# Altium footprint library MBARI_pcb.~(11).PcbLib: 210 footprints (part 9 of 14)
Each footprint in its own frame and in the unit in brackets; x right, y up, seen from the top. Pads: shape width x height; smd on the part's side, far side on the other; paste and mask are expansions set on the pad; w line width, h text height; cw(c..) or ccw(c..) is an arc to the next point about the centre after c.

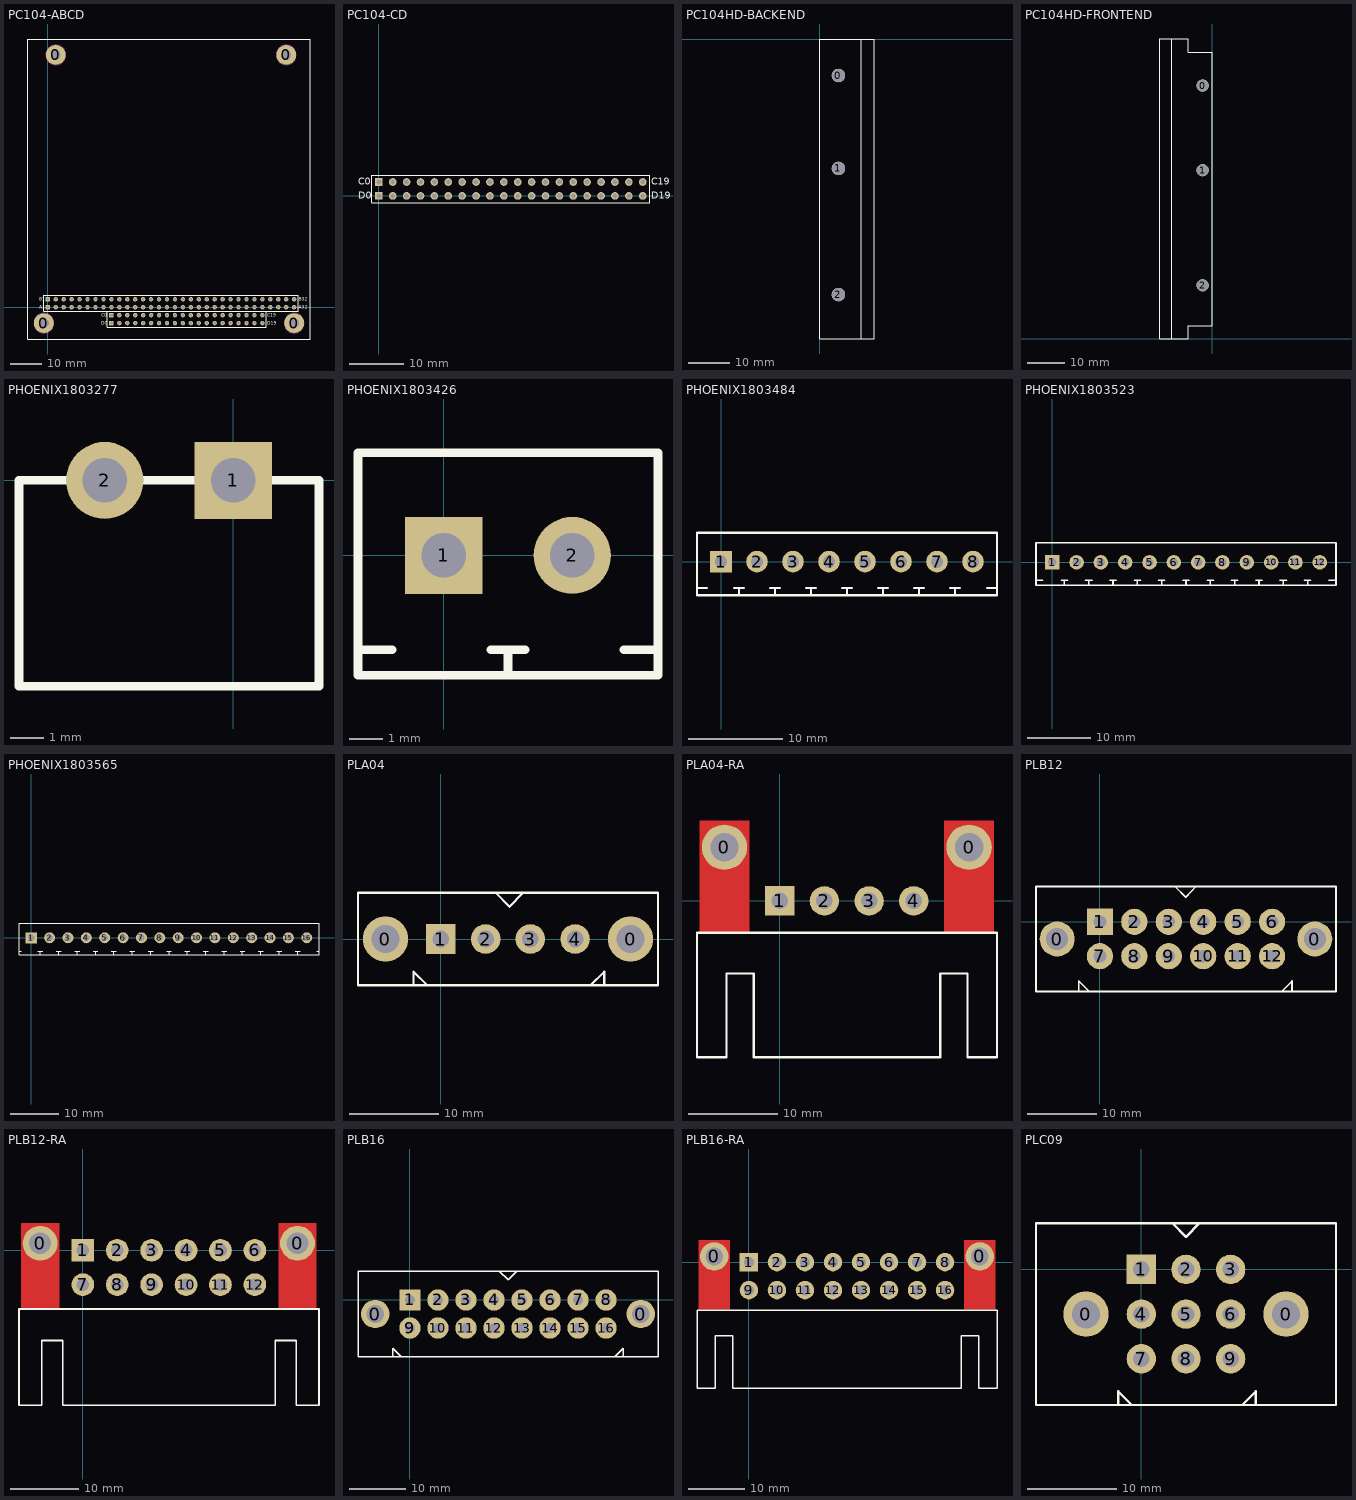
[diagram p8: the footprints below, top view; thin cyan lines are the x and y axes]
## PC104-ABCD [mil] "PC104 Outline and ABCD Rails"
height 600
pads (108):
  round 250 hole 125: 0(-50,-200) 0(100,3175) 0(3000,3175) 0(3100,-200)
  rect 55x55 hole 35: A1(0,0) B1(0,100) C0(800,-100) D0(800,-200)
  round 55 hole 35: A2(100,0) A3(200,0) A4(300,0) A5(400,0) A6(500,0) A7(600,0) A8(700,0) A9(800,0) A10(900,0) A11(1000,0) A12(1100,0) A13(1200,0) A14(1300,0) A15(1400,0) A16(1500,0) A17(1600,0) A18(1700,0) A19(1800,0) A20(1900,0) A21(2000,0) A22(2100,0) A23(2200,0) A24(2300,0) A25(2400,0) A26(2500,0) A27(2600,0) A28(2700,0) A29(2800,0) A30(2900,0) A31(3000,0) A32(3100,0) B2(100,100) B3(200,100) B4(300,100) B5(400,100) B6(500,100) B7(600,100) B8(700,100) B9(800,100) B10(900,100) B11(1000,100) B12(1100,100) B13(1200,100) B14(1300,100) B15(1400,100) B16(1500,100) B17(1600,100) B18(1700,100) B19(1800,100) B20(1900,100) B21(2000,100) B22(2100,100) B23(2200,100) B24(2300,100) B25(2400,100) B26(2500,100) B27(2600,100) B28(2700,100) B29(2800,100) B30(2900,100) B31(3000,100) B32(3100,100) C1(900,-100) C2(1000,-100) C3(1100,-100) C4(1200,-100) C5(1300,-100) C6(1400,-100) C7(1500,-100) C8(1600,-100) C9(1700,-100) C10(1800,-100) C11(1900,-100) C12(2000,-100) C13(2100,-100) C14(2200,-100) C15(2300,-100) C16(2400,-100) C17(2500,-100) C18(2600,-100) C19(2700,-100) D1(900,-200) D2(1000,-200) D3(1100,-200) D4(1200,-200) D5(1300,-200) D6(1400,-200) D7(1500,-200) D8(1600,-200) D9(1700,-200) D10(1800,-200) D11(1900,-200) D12(2000,-200) D13(2100,-200) D14(2200,-200) D15(2300,-200) D16(2400,-200) D17(2500,-200) D18(2600,-200) D19(2700,-200)
TopOverlay:
  lines w8: 3150,-50.39 3150,149.61 ; 3150,-50 -50,-50.39 -50,149.61 3150,150 ; 750,-250.39 2750,-250 2750,-50 750,-50.39 750,-250.39
  lines w10: -250,-400 3300,-400 3300,3375 -250,3375 -250,-400
  text "B1" at -110,80 h40
  text "A1" at -110,-20 h40
  text "A32" at 3160,-20.39 h40
  text "B32" at 3160,79.61 h40
  text "C19" at 2760,-120.39 h40
  text "D19" at 2760,-220.39 h40
  text "D0" at 670,-220 h40
  text "C0" at 670,-120 h40
KeepOutLayer:
  circle w10: c3100,-200 r125
  circle w10: c3000,3175 r125
  circle w10: c100,3175 r125
  circle w10: c-50,-200 r125

## PC104-CD [mil] "PC/104 C&D rails"
height 440
pads (40):
  rect 55x55 hole 35: C0(0,100) D0(0,0)
  round 55 hole 35: C1(100,100) C2(200,100) C3(300,100) C4(400,100) C5(500,100) C6(600,100) C7(700,100) C8(800,100) C9(900,100) C10(1000,100) C11(1100,100) C12(1200,100) C13(1300,100) C14(1400,100) C15(1500,100) C16(1600,100) C17(1700,100) C18(1800,100) C19(1900,100) D1(100,0) D2(200,0) D3(300,0) D4(400,0) D5(500,0) D6(600,0) D7(700,0) D8(800,0) D9(900,0) D10(1000,0) D11(1100,0) D12(1200,0) D13(1300,0) D14(1400,0) D15(1500,0) D16(1600,0) D17(1700,0) D18(1800,0) D19(1900,0)
TopOverlay:
  lines w8: -50,-50.39 1950,-50 1950,150 -50,149.61 -50,-50.39
  text "C19" at 1960,79.61 h50
  text "D19" at 1960,-20.39 h50
  text "D0" at -150,-20 h50
  text "C0" at -150,80 h50

## PC104HD-BACKEND [mil] "PC104 HardDrive Mount for Back End"
height 560
pads (3):
  round 130 hole 125: 0(180,-350) 1(180,-1240) 2(180,-2450)
TopOverlay:
  lines w10: 400,-2875 400,0 ; 0,-2875 525,-2875 525,0 0,0 0,-2875

## PC104HD-FRONTEND [mil] "PC104 HardDrive Mount Front End"
height 530
pads (3):
  round 130 hole 125: 0(-100,2665) 1(-100,1775) 2(-100,565)
TopOverlay:
  lines w10: -425,0 -425,3155 ; -550,0 -250,0 -250,140 0,140 0,3015 -250,3015 -250,3155 -550,3155 -550,0

## PHOENIX1803277 [mil]
pads (2):
  rect 90x90 hole 52: 1(0,0)
  round 90 hole 52: 2(-150,0)
TopOverlay:
  lines w10: -250,-240 -250,0 100,0 100,-240 -250,-240

## PHOENIX1803426 [mil]
pads (2):
  rect 90x90 hole 52: 1(0,0)
  round 90 hole 52: 2(150,0)
TopOverlay:
  lines w10: -100,-110 -60,-110 ; 55,-110 95,-110 ; 75,-140 75,-110 ; 210,-110 250,-110 ; -100,-140 250,-140 250,120 -100,120 -100,-140

## PHOENIX1803484 [mil]
pads (8):
  rect 90x90 hole 52: 1(0,0)
  round 90 hole 52: 2(150,0) 3(300,0) 4(450,0) 5(600,0) 6(750,0) 7(900,0) 8(1050,0)
TopOverlay:
  lines w10: -100,-110 -60,-110 ; 55,-110 95,-110 ; 75,-140 75,-110 ; 205,-110 245,-110 ; 225,-140 225,-110 ; 355,-110 395,-110 ; 375,-140 375,-110 ; 505,-110 545,-110 ; 525,-140 525,-110 ; 655,-110 695,-110 ; 675,-140 675,-110 ; 805,-110 845,-110 ; 825,-140 825,-110 ; 955,-110 995,-110 ; 975,-140 975,-110 ; 1110,-110 1150,-110 ; -100,-140 -100,120 1150,120 1150,-140 -100,-140

## PHOENIX1803523 [mil]
pads (12):
  rect 90x90 hole 52: 1(0,0)
  round 90 hole 52: 2(150,0) 3(300,0) 4(450,0) 5(600,0) 6(750,0) 7(900,0) 8(1050,0) 9(1200,0) 10(1350,0) 11(1500,0) 12(1650,0)
TopOverlay:
  lines w10: -100,-110 -60,-110 ; 55,-110 95,-110 ; 75,-140 75,-110 ; 205,-110 245,-110 ; 225,-140 225,-110 ; 355,-110 395,-110 ; 375,-140 375,-110 ; 505,-110 545,-110 ; 525,-140 525,-110 ; 655,-110 695,-110 ; 675,-140 675,-110 ; 805,-110 845,-110 ; 825,-140 825,-110 ; 955,-110 995,-110 ; 975,-140 975,-110 ; 1105,-110 1145,-110 ; 1125,-140 1125,-110 ; 1255,-110 1295,-110 ; 1275,-140 1275,-110 ; 1405,-110 1445,-110 ; 1425,-140 1425,-110 ; 1555,-110 1595,-110 ; 1575,-140 1575,-110 ; 1705,-110 1745,-110 ; -100,-140 -100,120 1750,120 1750,-140 -100,-140

## PHOENIX1803565 [mil]
pads (16):
  rect 90x90 hole 52: 1(0,0)
  round 90 hole 52: 2(150,0) 3(300,0) 4(450,0) 5(600,0) 6(750,0) 7(900,0) 8(1050,0) 9(1200,0) 10(1350,0) 11(1500,0) 12(1650,0) 13(1800,0) 14(1950,0) 15(2100,0) 16(2250,0)
TopOverlay:
  lines w10: -100,-110 -80,-110 ; 55,-110 95,-110 ; 75,-140 75,-110 ; 205,-110 245,-110 ; 225,-140 225,-110 ; 355,-110 395,-110 ; 375,-140 375,-110 ; 505,-110 545,-110 ; 525,-140 525,-110 ; 655,-110 695,-110 ; 675,-140 675,-110 ; 805,-110 845,-110 ; 825,-140 825,-110 ; 955,-110 995,-110 ; 975,-140 975,-110 ; 1105,-110 1145,-110 ; 1125,-140 1125,-110 ; 1255,-110 1295,-110 ; 1275,-140 1275,-110 ; 1405,-110 1445,-110 ; 1425,-140 1425,-110 ; 1555,-110 1595,-110 ; 1575,-140 1575,-110 ; 1705,-110 1745,-110 ; 1725,-140 1725,-110 ; 1855,-110 1895,-110 ; 1875,-140 1875,-110 ; 2005,-110 2045,-110 ; 2025,-140 2025,-110 ; 2155,-110 2195,-110 ; 2175,-140 2175,-110 ; 2330,-110 2350,-110 ; -100,-140 2350,-140 2350,120 -100,120 -100,-140

## PLA04 [mil] "Positronic 1x4 pin"
pads (6):
  round 200 hole 125: 0(-244.5,0) 0(835.5,0)
  rect 130x130 hole 73: 1(0,0)
  round 130 hole 73: 2(197,0) 3(394,0) 4(591,0)
TopOverlay:
  lines w10: -120.5,-204 -120.5,-144 -60.5,-204 ; 242,204 302.5,142.5 362,204 ; 659.5,-204 719.5,-144 719.5,-204 ; -365.5,-204 -365.5,204 956.5,204 956.5,-204 -365.5,-204

## PLA04-RA [mil]
pads (6):
  round 200 hole 125: 0(-244.5,237) 0(835.5,237)
  rect 130x130 hole 73: 1(0,0)
  round 130 hole 73: 2(197,0) 3(394,0) 4(591,0)
TopLayer:
  rectangle: 725.5,-138 945.5,354
  rectangle: -354.5,-138 -134.5,354
TopOverlay:
  lines w10: -365.5,-690 -235.5,-690 -235.5,-320 -115.5,-320 -115.5,-690 708.5,-690 708.5,-320 828.5,-320 828.5,-690 958.5,-690 958.5,-140 -365.5,-140 -365.5,-690

## PLB12 [mil] "Positronic 2x6 pin"
pads (14):
  round 200 hole 125: 0(-244.5,-98.5) 0(1229.5,-98.5)
  rect 150x150 hole 73: 1(0,0)
  round 150 hole 73: 2(197,0) 3(394,0) 4(591,0) 5(788,0) 6(985,0) 7(0,-197) 8(197,-197) 9(394,-197) 10(591,-197) 11(788,-197) 12(985,-197)
TopOverlay:
  lines w10: -120.5,-398.5 -120.5,-338.5 -60.5,-398.5 ; 429.5,201.5 490,140 549.5,201.5 ; 1039.5,-398.5 1099.5,-338.5 1099.5,-398.5 ; -365.5,-398.5 1350.5,-398.5 1350.5,201.5 -365.5,201.5 -365.5,-398.5

## PLB12-RA [mil]
pads (14):
  round 200 hole 125: 0(-244.5,40) 0(1229.5,40)
  rect 130x130 hole 73: 1(0,0)
  round 130 hole 73: 2(197,0) 3(394,0) 4(591,0) 5(788,0) 6(985,0) 7(0,-197) 8(197,-197) 9(394,-197) 10(591,-197) 11(788,-197) 12(985,-197)
TopLayer:
  rectangle: -354.5,-335 -134.5,157
  rectangle: 1119.5,-335 1339.5,157
TopOverlay:
  lines w10: -365.5,-887 -365.5,-337 1352.5,-337 1352.5,-887 1222.5,-887 1222.5,-517 1102.5,-517 1102.5,-887 -115.5,-887 -115.5,-517 -235.5,-517 -235.5,-887 -365.5,-887

## PLB16 [mil] "Positronic 2x8 pins"
pads (18):
  round 200 hole 125: 0(-244.5,-98.5) 0(1623.5,-98.5)
  rect 150x150 hole 73: 1(0,0)
  round 150 hole 73: 2(197,0) 3(394,0) 4(591,0) 5(788,0) 6(985,0) 7(1182,0) 8(1379,0) 9(0,-197) 10(197,-197) 11(394,-197) 12(591,-197) 13(788,-197) 14(985,-197) 15(1182,-197) 16(1379,-197)
TopOverlay:
  lines w10: -120.5,-398.5 -120.5,-338.5 -60.5,-398.5 ; 629.5,201.5 689.5,141.5 749.5,201.5 ; 1439.5,-398.5 1499.5,-338.5 1499.5,-398.5 ; -365.5,-398.5 1744.5,-398.5 1744.5,201.5 -365.5,201.5 -365.5,-398.5

## PLB16-RA [mil]
pads (18):
  round 200 hole 125: 0(-244.5,40) 0(1623.5,40)
  rect 130x130 hole 73: 1(0,0)
  round 130 hole 73: 2(197,0) 3(394,0) 4(591,0) 5(788,0) 6(985,0) 7(1182,0) 8(1379,0) 9(0,-197) 10(197,-197) 11(394,-197) 12(591,-197) 13(788,-197) 14(985,-197) 15(1182,-197) 16(1379,-197)
TopLayer:
  rectangle: -354.5,-335 -134.5,157
  rectangle: 1513.5,-335 1733.5,157
TopOverlay:
  lines w10: -365.5,-887 -365.5,-337 1744.5,-337 1744.5,-887 1614.5,-887 1614.5,-517 1494.5,-517 1494.5,-887 -115.5,-887 -115.5,-517 -235.5,-517 -235.5,-887 -365.5,-887

## PLC09 [mil] "Positronic 3x3 pins"
pads (11):
  round 200 hole 125: 0(-244.5,-197) 0(638.5,-197)
  rect 130x130 hole 73: 1(0,0)
  round 130 hole 73: 2(197,0) 3(394,0) 4(0,-197) 5(197,-197) 6(394,-197) 7(0,-394) 8(197,-394) 9(394,-394)
TopOverlay:
  lines w10: -102,-598 -102,-538 -42,-598 ; 136.5,205 197,143.5 256.5,205 ; 445,-598 505,-538 505,-598 ; -465,-598 -465,204 859,204 859,-598 -465,-598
